# Generated PnR-only RO_tune6 LEF access patch.
# Source LEF: /group/validmgr/PROJET/Prj_xh018/ksabra/lef/RO_tune6.lef
# Audit TSV: /sim/ksabra/SPADMIC_work/innovus/20260630_mptdc_mesh_bypass_broken_ro_probe_route_v1/local_route_drc_probe/ro_marker_vs_lef_oriented.tsv
# Generated UTC: 2026-06-30T13:20:03.490120+00:00
# Reason: split only OBS rectangles that overlap route DRC marker access windows.
# This is not golden layout source; use only through O1_RO_LEF_PATH for PnR diagnosis/closure.
VERSION 5.8 ;
BUSBITCHARS "[]" ;
DIVIDERCHAR "/" ;

PROPERTYDEFINITIONS
  MACRO CatenaDesignType STRING ;
END PROPERTYDEFINITIONS

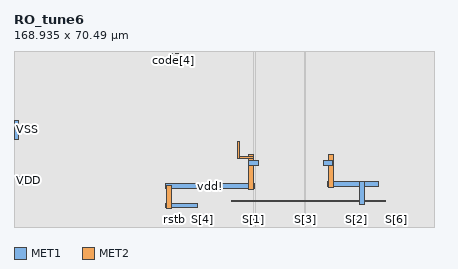
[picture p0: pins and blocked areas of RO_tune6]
MACRO RO_tune6
  CLASS BLOCK ;
  ORIGIN 68.695 88.51 ;
  FOREIGN RO_tune6 -68.695 -88.51 ;
  SIZE 168.935 BY 70.49 ;
  SYMMETRY X Y R90 ;
  PIN code[0]
    DIRECTION INPUT ;
    USE SIGNAL ;
    PORT
      LAYER MET1 ;
        RECT -2.775 -18.885 -2.545 -18.655 ;
    END
  END code[0]
  PIN code[7]
    DIRECTION INPUT ;
    USE SIGNAL ;
    PORT
      LAYER MET1 ;
        RECT -1.805 -18.885 -1.575 -18.655 ;
    END
  END code[7]
  PIN S[0]
    DIRECTION OUTPUT ;
    USE SIGNAL ;
    PORT
      LAYER MET2 ;
        RECT 23.305 -85.825 23.585 -85.545 ;
    END
  END S[0]
  PIN S[7]
    DIRECTION OUTPUT ;
    USE SIGNAL ;
    PORT
      LAYER MET2 ;
        RECT 64.455 -85.825 64.735 -85.545 ;
    END
  END S[7]
  PIN rstb
    DIRECTION INPUT ;
    USE SIGNAL ;
    PORT
      LAYER MET2 ;
        RECT -4.295 -85.825 -4.015 -85.545 ;
    END
  END rstb
  PIN code[1]
    DIRECTION INPUT ;
    USE SIGNAL ;
    PORT
      LAYER MET1 ;
        RECT -3.26 -18.885 -3.03 -18.655 ;
    END
  END code[1]
  PIN code[2]
    DIRECTION INPUT ;
    USE SIGNAL ;
    PORT
      LAYER MET1 ;
        RECT -3.745 -18.885 -3.515 -18.655 ;
    END
  END code[2]
  PIN code[3]
    DIRECTION INPUT ;
    USE SIGNAL ;
    PORT
      LAYER MET1 ;
        RECT -4.23 -18.885 -4 -18.655 ;
    END
  END code[3]
  PIN code[4]
    DIRECTION INPUT ;
    USE SIGNAL ;
    PORT
      LAYER MET1 ;
        RECT -4.715 -18.885 -4.485 -18.655 ;
    END
  END code[4]
  PIN code[5]
    DIRECTION INPUT ;
    USE SIGNAL ;
    PORT
      LAYER MET1 ;
        RECT -5.2 -18.885 -4.97 -18.655 ;
    END
  END code[5]
  PIN code[6]
    DIRECTION INPUT ;
    USE SIGNAL ;
    PORT
      LAYER MET1 ;
        RECT -2.29 -18.885 -2.06 -18.655 ;
    END
  END code[6]
  PIN VDD
    DIRECTION INOUT ;
    USE POWER ;
    PORT
      LAYER MET1 ;
        RECT -66.67 -71.56 -61.525 -68.325 ;
    END
  END VDD
  PIN VSS
    DIRECTION INOUT ;
    USE GROUND ;
    PORT
      LAYER MET1 ;
        RECT -68.695 -53.315 -67.015 -45.65 ;
    END
  END VSS
  PIN S[2]
    DIRECTION OUTPUT ;
    USE SIGNAL ;
    PORT
      LAYER MET2 ;
        RECT 68.805 -85.825 69.085 -85.545 ;
    END
  END S[2]
  PIN S[6]
    DIRECTION OUTPUT ;
    USE SIGNAL ;
    PORT
      LAYER MET2 ;
        RECT 85.03 -85.825 85.31 -85.545 ;
    END
  END S[6]
  PIN S[3]
    DIRECTION OUTPUT ;
    USE SIGNAL ;
    PORT
      LAYER MET2 ;
        RECT 48.23 -85.825 48.51 -85.545 ;
    END
  END S[3]
  PIN S[1]
    DIRECTION OUTPUT ;
    USE SIGNAL ;
    PORT
      LAYER MET2 ;
        RECT 27.655 -85.825 27.935 -85.545 ;
    END
  END S[1]
  PIN S[5]
    DIRECTION OUTPUT ;
    USE SIGNAL ;
    PORT
      LAYER MET2 ;
        RECT 43.91 -85.825 44.19 -85.545 ;
    END
  END S[5]
  PIN S[4]
    DIRECTION OUTPUT ;
    USE SIGNAL ;
    PORT
      LAYER MET2 ;
        RECT 7.08 -85.825 7.36 -85.545 ;
    END
  END S[4]
  PIN vdd!
    DIRECTION INOUT ;
    USE POWER ;
    PORT
      LAYER MET2 ;
        RECT 25.78 -73.255 27.78 -59.46 ;
        RECT 21.03 -60.815 27.78 -60.015 ;
        RECT 21.03 -60.815 21.83 -54.18 ;
        RECT -7.5 -80.96 -5.5 -71.79 ;
      LAYER MET1 ;
        RECT 25.805 -63.785 29.495 -61.785 ;
        RECT -7.605 -73.21 28.195 -71.21 ;
        RECT -7.62 -80.8 4.945 -79.16 ;
    END
    PORT
      LAYER MET2 ;
        RECT 57.7 -72.485 59.7 -59.46 ;
      LAYER MET1 ;
        RECT 18.875 -78.355 80.77 -78.015 ;
        RECT 57.28 -72.35 78.08 -70.35 ;
        RECT 70.155 -79.265 72.155 -70.35 ;
        RECT 55.885 -63.785 59.575 -61.785 ;
    END
  END vdd!
  OBS
    LAYER MET1 ;
      RECT 99.25 -67.175 99.55 -57.125 ;
      RECT 98.13 -67.175 98.43 -57.125 ;
      RECT 97.01 -67.175 97.31 -57.125 ;
      RECT 95.89 -67.175 96.19 -57.125 ;
      RECT 95.76 -67.175 100.24 -66.755 ;
      RECT 99.81 -66.425 100.11 -46.325 ;
      RECT 98.69 -66.425 98.99 -46.325 ;
      RECT 97.57 -66.425 97.87 -46.325 ;
      RECT 96.45 -66.425 96.75 -46.325 ;
      RECT 95.76 -56.795 100.24 -55.955 ;
      RECT 99.25 -55.625 99.55 -35.525 ;
      RECT 98.13 -55.625 98.43 -35.525 ;
      RECT 97.01 -55.625 97.31 -35.525 ;
      RECT 95.89 -55.625 96.19 -35.525 ;
      RECT 95.76 -45.995 100.24 -45.155 ;
      RECT 99.81 -44.825 100.11 -24.725 ;
      RECT 98.69 -44.825 98.99 -24.725 ;
      RECT 97.57 -44.825 97.87 -24.725 ;
      RECT 96.45 -44.825 96.75 -24.725 ;
      RECT 95.76 -35.195 100.24 -34.355 ;
      RECT 95.76 -24.395 100.24 -23.975 ;
      RECT 99.25 -34.025 99.55 -23.975 ;
      RECT 98.13 -34.025 98.43 -23.975 ;
      RECT 97.01 -34.025 97.31 -23.975 ;
      RECT 95.89 -34.025 96.19 -23.975 ;
      RECT -1.805 -23.44 -1.575 -19.485 ;
      RECT -24.275 -23.465 -23.895 -23.185 ;
      RECT -24.275 -23.44 -1.575 -23.21 ;
      RECT -2.29 -22.955 -2.06 -19.485 ;
      RECT -29.065 -22.98 -28.685 -22.7 ;
      RECT -29.065 -22.955 -2.06 -22.725 ;
      RECT -2.775 -22.47 -2.545 -19.485 ;
      RECT -33.855 -22.495 -33.475 -22.215 ;
      RECT -33.855 -22.47 -2.545 -22.24 ;
      RECT -3.26 -21.985 -3.03 -19.485 ;
      RECT -38.645 -22.01 -38.265 -21.73 ;
      RECT -38.645 -21.985 -3.03 -21.755 ;
      RECT -3.745 -21.5 -3.515 -19.485 ;
      RECT -43.435 -21.525 -43.055 -21.245 ;
      RECT -43.435 -21.5 -3.515 -21.27 ;
      RECT -4.23 -21.015 -4 -19.485 ;
      RECT -48.285 -21.04 -47.905 -20.76 ;
      RECT -48.285 -21.015 -4 -20.785 ;
      RECT -4.715 -20.53 -4.485 -19.485 ;
      RECT -53.1 -20.555 -52.72 -20.275 ;
      RECT -53.1 -20.53 -4.485 -20.3 ;
      RECT -5.2 -20.045 -4.97 -19.485 ;
      RECT -57.805 -20.07 -57.425 -19.79 ;
      RECT -57.805 -20.045 -4.97 -19.815 ;
      RECT -68.695 -83.02 -67.015 -53.915 ;
      RECT -68.695 -83.02 -8.41 -78.02 ;
      RECT -66.67 -67.725 -64.99 -36.465 ;
      RECT -68.695 -45.05 -67.015 -36.465 ;
    LAYER MET1 SPACING 0.23 ;
      RECT -1.155 -61.365 100.24 -18.02 ;
      RECT 81.19 -88.51 100.24 -18.02 ;
      RECT -68.695 -45.23 -5.62 -18.02 ;
      RECT -66.67 -61.365 100.24 -19.305 ;
      RECT -68.695 -67.905 25.385 -53.735 ;
      RECT 59.995 -69.93 100.24 -18.02 ;
      RECT 78.5 -77.595 100.24 -18.02 ;
      RECT 29.915 -77.595 55.465 -18.02 ;
      RECT -61.105 -69.93 100.24 -64.205 ;
      RECT -68.695 -88.51 -67.015 -53.735 ;
      RECT -61.105 -70.79 56.86 -64.205 ;
      RECT 28.615 -77.595 56.86 -64.205 ;
      RECT -61.105 -78.74 -8.025 -18.02 ;
      RECT -68.695 -88.51 -8.04 -71.98 ;
      RECT 72.575 -77.595 100.24 -72.77 ;
      RECT 28.615 -77.595 69.735 -72.77 ;
      RECT -68.695 -77.595 69.735 -73.63 ;
      RECT -68.695 -78.74 18.455 -73.63 ;
      RECT 5.365 -88.51 18.455 -73.63 ;
      RECT 77.03 -88.51 78.64 -78.675 ;
      RECT 56.455 -88.51 58.065 -78.675 ;
      RECT 35.88 -88.51 37.49 -78.675 ;
      RECT 72.575 -88.51 100.24 -78.775 ;
      RECT 5.365 -88.51 69.735 -78.775 ;
      RECT 5.365 -88.51 100.24 -79.685 ;
      RECT -68.695 -88.51 100.24 -81.22 ;
    LAYER MET2 ;
      RECT 99.26 -67.175 99.54 -57.125 ;
      RECT 98.14 -67.175 98.42 -57.125 ;
      RECT 97.02 -67.175 97.3 -57.125 ;
      RECT 95.9 -67.175 96.18 -57.125 ;
      RECT 95.76 -67.175 100.24 -66.775 ;
      RECT 99.82 -66.425 100.1 -46.325 ;
      RECT 98.7 -66.425 98.98 -46.325 ;
      RECT 97.58 -66.425 97.86 -46.325 ;
      RECT 96.46 -66.425 96.74 -46.325 ;
      RECT 95.76 -56.775 100.24 -55.975 ;
      RECT 99.26 -55.625 99.54 -35.525 ;
      RECT 98.14 -55.625 98.42 -35.525 ;
      RECT 97.02 -55.625 97.3 -35.525 ;
      RECT 95.9 -55.625 96.18 -35.525 ;
      RECT 95.76 -45.975 100.24 -45.175 ;
      RECT 99.82 -44.825 100.1 -24.725 ;
      RECT 98.7 -44.825 98.98 -24.725 ;
      RECT 97.58 -44.825 97.86 -24.725 ;
      RECT 96.46 -44.825 96.74 -24.725 ;
      RECT 95.76 -35.175 100.24 -34.375 ;
      RECT 95.76 -24.375 100.24 -23.975 ;
      RECT 99.26 -34.025 99.54 -23.975 ;
      RECT 98.14 -34.025 98.42 -23.975 ;
      RECT 97.02 -34.025 97.3 -23.975 ;
      RECT 95.9 -34.025 96.18 -23.975 ;
      RECT -68.64 -50.215 -63.035 -47.215 ;
      RECT -68.64 -58.215 -63.415 -55.215 ;
      RECT -68.64 -66.215 -63.575 -63.215 ;
    LAYER MET2 SPACING 0.28 ;
      RECT -68.695 -45.23 100.24 -18.02 ;
      RECT 85.73 -88.51 100.24 -18.02 ;
      RECT -66.595 -53.76 100.24 -18.02 ;
      RECT 81.19 -85.125 100.24 -18.02 ;
      RECT -68.64 -50.215 100.24 -47.215 ;
      RECT -68.695 -67.905 20.705 -53.735 ;
      RECT 22.25 -59.04 100.24 -18.02 ;
      RECT 78.5 -77.595 100.24 -18.02 ;
      RECT 60.12 -69.93 100.24 -18.02 ;
      RECT 28.2 -61.365 57.28 -18.02 ;
      RECT 22.25 -59.595 25.36 -18.02 ;
      RECT -61.105 -70.79 25.36 -61.235 ;
      RECT 29.915 -77.595 55.465 -18.02 ;
      RECT 28.2 -69.93 57.28 -64.205 ;
      RECT -68.695 -88.51 -67.09 -53.735 ;
      RECT 28.2 -70.79 56.86 -64.205 ;
      RECT 28.615 -77.595 56.86 -64.205 ;
      RECT -61.105 -78.74 -8.025 -18.02 ;
      RECT -68.695 -88.51 -8.04 -71.98 ;
      RECT 72.575 -77.595 100.24 -72.77 ;
      RECT 60.12 -77.595 69.735 -72.77 ;
      RECT 28.615 -77.595 57.28 -72.77 ;
      RECT 28.615 -77.595 69.735 -72.905 ;
      RECT 28.2 -77.595 69.735 -73.63 ;
      RECT -5.08 -77.595 25.36 -73.63 ;
      RECT -68.695 -78.74 -7.92 -73.63 ;
      RECT -5.08 -77.595 69.735 -73.675 ;
      RECT -5.08 -74.215 100.24 -73.935 ;
      RECT -5.08 -75.1 100.24 -74.82 ;
      RECT 80.18 -88.51 80.46 -18.02 ;
      RECT 74.585 -78.075 75.44 -72.77 ;
      RECT 75.16 -88.51 75.44 -72.77 ;
      RECT 73.805 -88.51 74.085 -72.77 ;
      RECT 59.605 -88.51 59.885 -72.905 ;
      RECT 54.585 -88.51 54.865 -18.02 ;
      RECT 53.23 -88.51 53.51 -18.02 ;
      RECT 51.4 -88.51 51.74 -18.02 ;
      RECT 38.975 -78.025 39.31 -18.02 ;
      RECT 39.03 -88.51 39.31 -18.02 ;
      RECT 34.01 -78.075 36.195 -18.02 ;
      RECT 32.655 -88.51 32.935 -18.02 ;
      RECT 30.825 -88.51 31.165 -18.02 ;
      RECT -5.08 -78.74 18.735 -73.63 ;
      RECT 71.975 -88.51 72.315 -77.775 ;
      RECT 34.01 -88.51 34.29 -18.02 ;
      RECT 5.365 -85.125 18.735 -73.63 ;
      RECT 4.115 -88.51 4.395 -73.63 ;
      RECT -4.295 -85.125 -4.015 -73.63 ;
      RECT 71.975 -85.125 100.24 -78.775 ;
      RECT 5.365 -85.125 69.735 -78.775 ;
      RECT 69.505 -88.51 84.61 -79.685 ;
      RECT -5.08 -85.125 100.24 -81.22 ;
      RECT -3.595 -88.51 6.66 -81.22 ;
      RECT -68.695 -88.51 -7.92 -81.22 ;
      RECT -68.695 -88.51 -4.715 -81.38 ;
      RECT 65.155 -88.51 68.385 -78.775 ;
      RECT 48.93 -88.51 64.035 -78.775 ;
      RECT 44.61 -88.51 47.81 -78.775 ;
      RECT 28.355 -88.51 43.49 -78.775 ;
      RECT 24.005 -88.51 27.235 -78.775 ;
      RECT 7.78 -88.51 22.885 -78.775 ;
      # MPTDC_PNR_ACCESS_TRIM original RECT -68.695 -88.51 100.24 -86.245 ;
      RECT -68.695 -88.51 -4.495 -86.245 ;
      RECT -3.815 -88.51 6.88 -86.245 ;
      RECT 7.56 -88.51 23.105 -86.245 ;
      RECT 23.785 -88.51 27.455 -86.245 ;
      RECT 28.245 -88.51 43.71 -86.245 ;
      RECT 44.39 -88.51 48.03 -86.245 ;
      RECT 48.71 -88.51 64.255 -86.245 ;
      RECT 64.935 -88.51 68.605 -86.245 ;
      RECT 69.285 -88.51 84.83 -86.245 ;
      RECT 85.51 -88.51 100.24 -86.245 ;
    LAYER MET3 ;
      RECT 99.26 -67.175 99.54 -57.325 ;
      RECT 98.14 -67.175 98.42 -57.325 ;
      RECT 97.02 -67.175 97.3 -57.325 ;
      RECT 95.9 -67.175 96.18 -57.325 ;
      RECT 95.76 -67.175 100.24 -66.575 ;
      RECT 99.82 -66.225 100.1 -46.525 ;
      RECT 98.7 -66.225 98.98 -46.525 ;
      RECT 97.58 -66.225 97.86 -46.525 ;
      RECT 96.46 -66.225 96.74 -46.525 ;
      RECT 95.76 -56.975 100.24 -55.775 ;
      RECT 99.26 -55.425 99.54 -35.725 ;
      RECT 98.14 -55.425 98.42 -35.725 ;
      RECT 97.02 -55.425 97.3 -35.725 ;
      RECT 95.9 -55.425 96.18 -35.725 ;
      RECT 95.76 -46.175 100.24 -44.975 ;
      RECT 99.82 -44.625 100.1 -24.925 ;
      RECT 98.7 -44.625 98.98 -24.925 ;
      RECT 97.58 -44.625 97.86 -24.925 ;
      RECT 96.46 -44.625 96.74 -24.925 ;
      RECT 95.76 -35.375 100.24 -34.175 ;
      RECT 95.76 -24.575 100.24 -23.975 ;
      RECT 99.26 -33.825 99.54 -23.975 ;
      RECT 98.14 -33.825 98.42 -23.975 ;
      RECT 97.02 -33.825 97.3 -23.975 ;
      RECT 95.9 -33.825 96.18 -23.975 ;
    LAYER MET3 SPACING 0.28 ;
      RECT -68.695 -53.76 100.24 -18.02 ;
      RECT 85.73 -88.51 100.24 -18.02 ;
      RECT 22.25 -59.04 100.24 -18.02 ;
      RECT 60.12 -85.125 100.24 -18.02 ;
      RECT -68.695 -71.37 20.61 -18.02 ;
      RECT 28.2 -85.125 57.28 -18.02 ;
      RECT 22.25 -59.595 25.36 -18.02 ;
      RECT -5.08 -85.125 25.36 -61.235 ;
      RECT -68.695 -88.51 -7.92 -18.02 ;
      RECT 48.93 -88.51 64.035 -72.905 ;
      RECT -5.08 -85.125 100.24 -73.675 ;
      RECT -68.695 -88.51 -4.715 -81.38 ;
      RECT 69.505 -88.51 84.61 -18.02 ;
      RECT 65.155 -88.51 68.385 -18.02 ;
      RECT 44.61 -88.51 47.81 -18.02 ;
      RECT 28.355 -88.51 43.49 -18.02 ;
      RECT 24.005 -88.51 27.235 -73.675 ;
      RECT 7.78 -88.51 22.885 -61.235 ;
      RECT -3.595 -88.51 6.66 -18.02 ;
      # MPTDC_PNR_ACCESS_TRIM original RECT -68.695 -88.51 100.24 -86.245 ;
      RECT -68.695 -88.51 27.455 -86.245 ;
      RECT 28.245 -88.51 48.03 -86.245 ;
      RECT 48.71 -88.51 100.24 -86.245 ;
    LAYER METTP SPACING 0.46 ;
      # MPTDC_PNR_ACCESS_TRIM original RECT -68.695 -88.51 100.24 -18.02 ;
      RECT -68.695 -88.51 27.455 -18.02 ;
      RECT 28.245 -88.51 48.03 -18.02 ;
      RECT 27.455 -85.345 28.245 -18.02 ;
      RECT 48.71 -88.51 100.24 -18.02 ;
      RECT 48.03 -85.345 48.71 -18.02 ;
  END
  PROPERTY CatenaDesignType "mixed" ;
END RO_tune6

END LIBRARY
